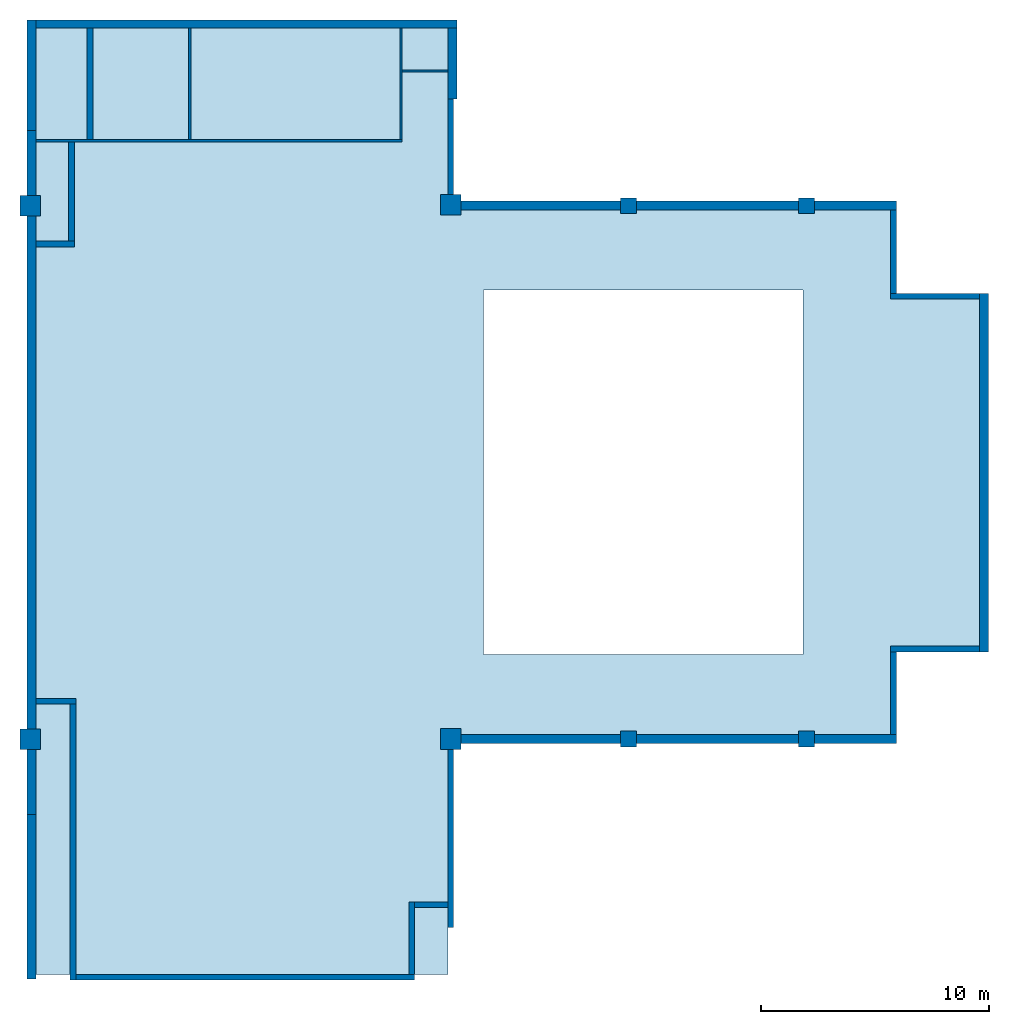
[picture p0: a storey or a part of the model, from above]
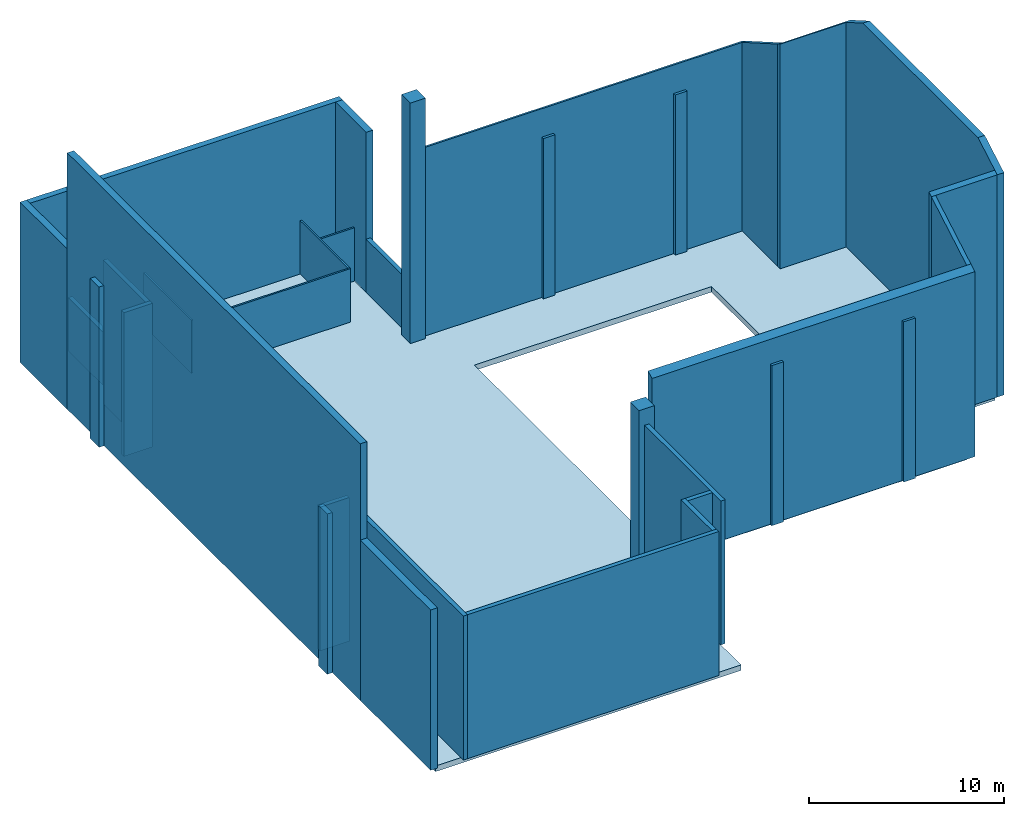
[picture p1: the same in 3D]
Properties of the parts of a building model (IFC2X3)

# File
Description: ViewDefinition [CoordinationView_V2.0], RevitIdentifiers [ContentGUID: 5fec9d22-f77b-40c9-8145-6ea0bd41274a, VersionGUID: 11239b1c-a36d-4747-897d-173505367494, NumberOfSaves: 46], CoordinateReference [CoordinateBase: Shared Coordinates, ProjectSite: NL_00_locatie]
File name: K176TT2132.ifc
Time: 2025-05-07T07:51:57+01:00
Written by: ODA SDAI 24.12
Made in: Autodesk Revit 25.4.10.45 (ENU) - IFC 25.4.10.45

# IfcProject, K176TT2132
LongName: Vervanging trekkenwand

# IfcSite, Default
RefLatitude: 52, 22, 22, 799999; RefLongitude: 4, 53, 41, 279999; RefElevation: 0 mm

# IfcBuilding
Pset_BuildingCommon - NumberOfStoreys: 6

# IfcBuildingStorey: Level:PBTA niveau met benaming (50)
Pset_AirSideSystemInformation - sets with these values: 2
Name | LongName = Name | Elevation (mm)
Peil | Peil | 0
Rij 1 | Rij 1 | 80
Rij 2 | Rij 2 | 160
Rij 3 | Rij 3 | 240
Rij 4 | Rij 4 | 320
Rij 5 | Rij 5 | 400
Rij 6 | Rij 6 | 480
Rij 7 | Rij 7 | 560
Rij 8 | Rij 8 | 640
Rij 9 | Rij 9 | 840
Rij 10 | Rij 10 | 1040
Rij 11 | Rij 11 | 1240
Rij 12 | Rij 12 | 1440
Rij 13 | Rij 13 | 1640
Rij 14 | Rij 14 | 1840
Rij 15 | Rij 15 | 2040
Rij 16 | Rij 16 | 2240
Rij 17 | Rij 17 | 2440
Rij 18 | Rij 18 | 2640
Rij 19 | Rij 19 | 2840
Rij 20 | Rij 20 | 3040
Rij 21 | Rij 21 | 3240
Rij 22 | Rij 22 | 3440
Rij 23 | Rij 23 | 3640
Rij 24 | Rij 24 | 3840
Rij 25 | Rij 25 | 4040
Balkon Rij 1 | Balkon Rij 1 | 5540
Balkon Rij 2 | Balkon Rij 2 | 5940
Balkon Rij 3 | Balkon Rij 3 | 6340
Balkon Rij 4 | Balkon Rij 4 | 6740
2e verdieping | 2e verdieping | 7050
Balkon Rij 5 | Balkon Rij 5 | 7140
Balkon Rij 6 | Balkon Rij 6 | 7540
Balkon Rij 7 | Balkon Rij 7 | 7940
Balkon Rij 8 | Balkon Rij 8 | 8340
Balkon Rij 9 | Balkon Rij 9 | 8740
Balkon Rij 10 | Balkon Rij 10 | 9140
Balkon Rij 11 | Balkon Rij 11 | 9540
Balkon Rij 12 | Balkon Rij 12 | 9940
Balkon Rij 13 | Balkon Rij 13 | 10340
3e verdieping | 3e verdieping | 10390
Balkon Rij 14 | Balkon Rij 14 | 10740
Balkon Rij 15 | Balkon Rij 15 | 11140
4e verdieping | 4e verdieping | 13730
5e verdieping | 5e verdieping | 17070
Dak binnendooszaal | Dak binnendooszaal | 22086.4
Dak zaal | Dak zaal | 23090
Rollenzolder | Rollenzolder | 30550
Dak toneeltoren | Dak toneeltoren | 33630
Dakrand toneeltoren | Dakrand toneeltoren | 34000

# IfcBeam: H-Balk:HEA140 (42)
Type - PredefinedType: BEAM
Type - Pset_BeamCommon - LoadBearing: yes
Material: Staal PBTA
Pset_BeamCommon - IsExternal: no; Slope: 0 deg; Reference: HEA140
Pset_QuantityTakeOff - Reference: HEA140; sets with these values: 2
Name (H-Balk:HEA140:...) | In | Span (mm)
577840 | Rollenzolder | 2960
578171 | Rollenzolder | 2960
578181 | Rollenzolder | 2960
578191 | Rollenzolder | 2960
578201 | Rollenzolder | 2960
578247 | Rollenzolder | 2960
578248 | Rollenzolder | 2960
578249 | Rollenzolder | 2960
578250 | Rollenzolder | 2960
578251 | Rollenzolder | 2960
579849 | Rollenzolder | 2958
579961 | Rollenzolder | 3017
579963 | Rollenzolder | 3017
579965 | Rollenzolder | 3017
579967 | Rollenzolder | 3017
579969 | Rollenzolder | 3017
579971 | Rollenzolder | 3017
579973 | Rollenzolder | 2958
579975 | Rollenzolder | 1517
580310 | Rollenzolder | 3017
580553 | Rollenzolder | 3017
580565 | Rollenzolder | 3017
580581 | Rollenzolder | 3017
580593 | Rollenzolder | 3017
580605 | Rollenzolder | 3017
580706 | Rollenzolder | 1517
642158 | Dak binnendooszaal | 2850
642609 | Dak binnendooszaal | 2850
642653 | Dak binnendooszaal | 2850
642667 | Dak binnendooszaal | 2850
642752 | Dak binnendooszaal | 2850
642753 | Dak binnendooszaal | 2850
642754 | Dak binnendooszaal | 2850
642755 | Dak binnendooszaal | 2850
642849 | Dak binnendooszaal | 2850
642850 | Dak binnendooszaal | 2850
642851 | Dak binnendooszaal | 2850
642852 | Dak binnendooszaal | 2850
642962 | Dak binnendooszaal | 2850
642963 | Dak binnendooszaal | 2850
642964 | Dak binnendooszaal | 2850
642965 | Dak binnendooszaal | 2850

# IfcBeam: H-Balk:HEA220 (4)
In: Dak binnendooszaal
Type - PredefinedType: BEAM
Type - Pset_BeamCommon - LoadBearing: yes
Material: Staal PBTA
Pset_BeamCommon - IsExternal: no; Slope: 0 deg; Reference: HEA220; Span: 5600 mm
Pset_QuantityTakeOff - Reference: HEA220; sets with these values: 2
Name (H-Balk:HEA220:...)
636427
636710
636720
636728

# IfcBeam: H-Balk:HEA240 (4)
In: Dak toneeltoren
Type - PredefinedType: BEAM
Type - Pset_BeamCommon - LoadBearing: yes
Material: Staal PBTA
Pset_BeamCommon - IsExternal: no; Reference: HEA240; Span: 29600 mm; Slope: 0 deg
Pset_QuantityTakeOff - Reference: HEA240; sets with these values: 2
Name (H-Balk:HEA240:...)
576049
576216
576222
576230

# IfcBeam: H-Balk:HEA300 (5)
In: Dak binnendooszaal
Type - PredefinedType: BEAM
Type - Pset_BeamCommon - LoadBearing: yes
Material: Staal PBTA
Pset_BeamCommon - IsExternal: no; Slope: 0 deg; Reference: HEA300; Span: 22745 mm
Pset_QuantityTakeOff - Reference: HEA300; sets with these values: 2
Name (H-Balk:HEA300:...)
627919
628030
628137
628199
628205

# IfcBeam: H-Balk:HEB240 (5)
In: Dak toneeltoren
Type - PredefinedType: BEAM
Type - Pset_BeamCommon - LoadBearing: yes
Material: Staal PBTA
Pset_BeamCommon - IsExternal: no; Slope: 0 deg; Reference: HEB240
Pset_QuantityTakeOff - Reference: HEB240; sets with these values: 2
Name (H-Balk:HEB240:...) | Span (mm)
576121 | 29600
576567 | 18200
576896 | 18200
576940 | 18200
576941 | 18200

# IfcBeam: IPE-Balk:IPE160 (134)
In: Rollenzolder
Type - PredefinedType: BEAM
Type - Pset_BeamCommon - LoadBearing: yes
Material: Staal PBTA
Pset_BeamCommon - IsExternal: no; Slope: 0 deg; Reference: IPE160
Pset_QuantityTakeOff - Reference: IPE160; sets with these values: 2
Name (IPE-Balk:IPE160:...) | Span (mm)
579442 | 2958
579553 | 2958
579662 | 1517
579663 | 1517
579728 | 3017
579729 | 3017
579780 | 3017
579781 | 3017
579789 | 3017
579790 | 3017
579800 | 3017
579801 | 3017
579809 | 3017
579810 | 3017
579822 | 3017
579823 | 3017
579850 | 2958
579851 | 1517
579852 | 1517
579878 | 2958
579879 | 2958
579880 | 1517
579881 | 1517
579882 | 3017
579883 | 3017
579884 | 3017
579885 | 3017
579886 | 3017
579887 | 3017
579888 | 3017
579889 | 3017
579890 | 3017
579891 | 3017
579892 | 3017
579893 | 3017
579894 | 2958
579895 | 2958
579896 | 1517
579897 | 1517
579905 | 2958
579906 | 2958
579907 | 1517
579908 | 1517
579909 | 3017
579910 | 3017
579911 | 3017
579912 | 3017
579913 | 3017
579914 | 3017
579915 | 3017
579916 | 3017
579917 | 3017
579918 | 3017
579919 | 3017
579920 | 3017
579921 | 2958
579922 | 2958
579923 | 1517
579924 | 1517
579930 | 2958
579931 | 2958
579932 | 1517
579933 | 1517
579934 | 3017
579935 | 3017
579936 | 3017
579937 | 3017
579938 | 3017
579939 | 3017
579940 | 3017
579941 | 3017
579942 | 3017
579943 | 3017
579944 | 3017
579945 | 3017
579946 | 2958
579947 | 2958
579948 | 1517
579949 | 1517
579957 | 2958
579959 | 1517
579999 | 2958
580000 | 2958
580001 | 1517
580002 | 1517
580003 | 3017
580004 | 3017
580005 | 3017
580006 | 3017
580007 | 3017
580008 | 3017
580009 | 3017
580010 | 3017
580011 | 3017
580012 | 3017
580013 | 3017
580014 | 3017
580015 | 2958
580016 | 2958
580017 | 1517
580018 | 1517
580399 | 1517
580400 | 1517
580401 | 1517
580402 | 1517
580403 | 1517
580485 | 3017
580486 | 3017
580487 | 3017
580488 | 3017
580554 | 3017
580555 | 3017
580556 | 3017
580557 | 3017
580566 | 3017
580567 | 3017
580568 | 3017
580569 | 3017
580582 | 3017
580583 | 3017
580584 | 3017
580585 | 3017
580594 | 3017
580595 | 3017
580596 | 3017
580597 | 3017
580606 | 3017
580607 | 3017
580608 | 3017
580609 | 3017
580703 | 1517
580704 | 1517
580705 | 1517
580707 | 1517

# IfcBuildingElementProxy: Decortrek Theater Rotterdam:L binnen (68)
In: Rollenzolder
Type - Material: Staal-PBTA, Staal-PBRI
Pset_BuildingElementProxyCommon - Reference: L binnen; sets with these values: 2
Name (Decortrek Theater Rotterdam:L binnen:...)
594433
595344
595345
595356
595357
595360
595361
595364
595365
595368
595369
595372
595373
595376
595377
595380
595381
595384
595385
595388
595389
595392
595393
595396
595397
595400
595401
595404
595405
595408
595409
595412
595413
595416
595417
595420
595421
595424
595425
595428
595429
595432
595433
595436
595437
595440
595441
595444
595445
595448
595449
595452
595453
595456
595457
595460
595461
595464
595465
595468
595469
595472
595473
595476
595477
595497
612826
612827

# IfcBuildingElementProxy: Lier bestaand:Lier centercluster, Lier bestaand:Lier centercluster:627696
In: 5e verdieping
Type - Material: Staal-PBRI
Pset_BuildingElementProxyCommon - Reference: Lier centercluster; sets with these values: 2

# IfcBuildingElementProxy: Lier bestaand:Lier portaalbrug, Lier bestaand:Lier portaalbrug:622974
In: Rollenzolder
Type - Material: Staal-PBRI
Pset_BuildingElementProxyCommon - Reference: Lier portaalbrug; sets with these values: 2

# IfcBuildingElementProxy: Proscenium trek Rotterdam:Proscenium trek Rotterdam, Proscenium trek Rotterdam:Proscenium trek Rotterdam:636032
In: Dak binnendooszaal
Type - Material: Staal-PBRI, Staal-PBTA
Pset_BuildingElementProxyCommon - Reference: Proscenium trek Rotterdam; sets with these values: 2

# IfcBuildingElementProxy: Spant:Spant (7)
In: Rollenzolder
Type - Material: Staal PBTA, <Unnamed>
Pset_BuildingElementProxyCommon - Reference: Spant; sets with these values: 2
Name (Spant:Spant:...)
569781
570149
570157
570165
570175
574750
574758

# IfcBuildingElementProxy: Zaaltrek Theater Rotterdam:Zaaltrek Theater Rotterdam (2)
In: Dak binnendooszaal
Type - Material: Staal-PBRI, Staal-PBTA
Pset_BuildingElementProxyCommon - Reference: Zaaltrek Theater Rotterdam; sets with these values: 2
Name (Zaaltrek Theater Rotterdam:Zaaltrek Theater Rotterdam:...)
606188
606455

# IfcBuildingElementProxy: Zijtrek Theater Rotterdam:R binnen (2)
In: Rollenzolder
Type - Material: Staal-PBRI, Staal-PBTA
Pset_BuildingElementProxyCommon - Reference: R binnen; sets with these values: 2
Name (Zijtrek Theater Rotterdam:R binnen:...)
618984
621021

# IfcBuildingElementProxy: Zijtrek Theater Rotterdam:R buiten (2)
In: Rollenzolder
Type - Material: Staal-PBRI, Staal-PBTA
Pset_BuildingElementProxyCommon - Reference: R buiten; sets with these values: 2
Name (Zijtrek Theater Rotterdam:R buiten:...)
619524
621022

# IfcBuildingElementProxy: ophanging:ophanging (2)
In: Rollenzolder
Type - Material: Staal PBTA
Pset_BuildingElementProxyCommon - Reference: ophanging; sets with these values: 2
Name (ophanging:ophanging:...)
574341
574693

# IfcColumn: Koker-Kolom:K80/80/4CF (8)
In: Dak binnendooszaal
Type - PredefinedType: COLUMN; Material: Staal PBTA
Type - Pset_ColumnCommon - LoadBearing: yes
Pset_ColumnCommon - IsExternal: no; Reference: K80/80/4CF
Pset_QuantityTakeOff - Reference: K80/80/4CF; sets with these values: 2
Name (Koker-Kolom:K80/80/4CF:...)
637413
637721
637804
637805
637818
637819
637836
637837

# IfcColumn: M_Concrete-Square-Column:700 x 700mm (4)
In: 2e verdieping
Type - PredefinedType: COLUMN; Material: Concrete, Cast-in-Place gray
Type - Pset_ColumnCommon - LoadBearing: yes
Pset_ColumnCommon - IsExternal: no; Reference: 700 x 700mm
Pset_QuantityTakeOff - Reference: 700 x 700mm; sets with these values: 2
Name (M_Concrete-Square-Column:700 x 700mm:...)
588921
589097
589205
589206

# IfcColumn: M_Concrete-Square-Column:900 x 900 (4)
In: 2e verdieping
Type - PredefinedType: COLUMN; Material: Concrete, Cast-in-Place gray
Type - Pset_ColumnCommon - LoadBearing: yes
Pset_ColumnCommon - IsExternal: no; Reference: 900 x 900
Pset_QuantityTakeOff - Reference: 900 x 900; sets with these values: 2
Name (M_Concrete-Square-Column:900 x 900:...)
563383
563395
563466
563523

# IfcDistributionPort (2)
Description: Flow; FlowDirection: SOURCEANDSINK
Name
Port_632358_0
Port_632358_1

# IfcDoor: Binnendeur enkel:780x2115, Binnendeur enkel:780x2115:598546
In: Rollenzolder
Type - OperationType: SINGLE_SWING_LEFT; ParameterTakesPrecedence: no; Sizeable: no; Material: Kozijn, Deur
Type - Binnendeur enkel:780x2115:598546:1 - PanelOperation: SWINGING
OverallHeight: 2187 mm; OverallWidth: 884 mm
Pset_DoorCommon - IsExternal: no; Reference: 780x2115
Pset_QuantityTakeOff - Reference: 780x2115

# IfcDoor: Binnendeur enkel:780x2115 (3)
In: Rollenzolder
Type - OperationType: SINGLE_SWING_RIGHT; ParameterTakesPrecedence: no; Sizeable: no; Material: Kozijn, Deur
Type - Binnendeur enkel:780x2115:598288:1 - PanelOperation: SWINGING
OverallHeight: 2187 mm; OverallWidth: 884 mm
Pset_DoorCommon - IsExternal: no; Reference: 780x2115
Pset_QuantityTakeOff - Reference: 780x2115
Name (Binnendeur enkel:780x2115:...)
598288
598549
599045

# IfcFlowSegment: Cable Tray without Fittings:Wire Mesh Cable Tray, Cable Tray without Fittings:Wire Mesh Cable Tray:632358
In: Dak binnendooszaal
Type - PredefinedType: CABLETRAYSEGMENT
Pset_DistributionFlowElementCommon - Reference: Wire Mesh Cable Tray; sets with these values: 2
Pset_FlowSegmentDuctSegment - Length: 10700 mm; sets with these values: 2

# IfcOpeningElement: Opening (5)
Name | In
Floor:NL_23 Toneelvloer:145068 | 2e verdieping | Pset_OpeningElementCommon - Reference: NL_23 Toneelvloer; sets with these values: 2
Binnendeur enkel:780x2115:598288:1 | Rollenzolder
Binnendeur enkel:780x2115:598549:1 | Rollenzolder
Binnendeur enkel:780x2115:598546:1 | Rollenzolder
Binnendeur enkel:780x2115:599045:1 | Rollenzolder

# IfcRoof: Basic Roof:NL_27_basis_200 (4)
Material: NL_27_dak 200 mm
Pset_QuantityTakeOff - Reference: NL_27_basis_200
Pset_RoofCommon - IsExternal: yes; Reference: NL_27_basis_200
Name (Basic Roof:NL_27_basis_200:...) | In | ProjectedArea (m2) | TotalArea (m2)
561494 | Dak binnendooszaal | 273.581 | 273.581
587362 | Dak toneeltoren | 547.748 | 547.748
600069 | Dak binnendooszaal | 123.194 | 142.252
600201 | Dak binnendooszaal | 123.268 | 142.338

# IfcSlab: Basic Roof:NL_27_basis_200 (4)
PredefinedType: ROOF; Material: NL_27_dak 200 mm
Pset_QuantityTakeOff - Reference: NL_27_basis_200; sets with these values: 2
Pset_SlabCommon - IsExternal: yes; Reference: NL_27_basis_200
Name (Basic Roof:NL_27_basis_200:...) | In | PitchAngle (deg)
561494 | Dak binnendooszaal | 0
587362 | Dak toneeltoren | 0
600069 | Dak binnendooszaal | 30
600201 | Dak binnendooszaal | 30

# IfcSlab: Floor:NL_23 Rooster bruggen (4)
In: 5e verdieping
Type - PredefinedType: FLOOR; Material: Roostervloer dicht 30 mm
Pset_QuantityTakeOff - Reference: NL_23 Rooster bruggen; sets with these values: 2
Pset_SlabCommon - LoadBearing: no; IsExternal: no; PitchAngle: 0 deg; Reference: NL_23 Rooster bruggen
Name (Floor:NL_23 Rooster bruggen:...)
599056
599094
599273
599353

# IfcSlab: Floor:NL_23 Toneelvloer, Floor:NL_23 Toneelvloer:563597
In: 2e verdieping
Type - PredefinedType: FLOOR; Material: NL_45 Keroewing 22 mm, NL_45 Multiplex 18 mm, NL_45 isolatie + regelwerk 10 mm, NL_23 Kanaalplaatvloer 300 mm
Pset_QuantityTakeOff - Reference: NL_23 Toneelvloer; sets with these values: 2
Pset_SlabCommon - LoadBearing: no; IsExternal: no; PitchAngle: 0 deg; Reference: NL_23 Toneelvloer

# IfcWallStandardCase: Basic Wall:AL_20_basis_100 (4)
In: 2e verdieping
Type - PredefinedType: STANDARD; Material: NL_20_wand 100 mm
Pset_QuantityTakeOff - Reference: AL_20_basis_100; sets with these values: 2
Pset_WallCommon - LoadBearing: no; IsExternal: no; ExtendToStructure: no; Reference: AL_20_basis_100
Name (Basic Wall:AL_20_basis_100:...)
562058
562084
562090
562096

# IfcWallStandardCase: Basic Wall:AL_20_basis_140 (3)
In: Rollenzolder
Type - PredefinedType: STANDARD; Material: NL_20_wand 140 mm
Pset_QuantityTakeOff - Reference: AL_20_basis_140; sets with these values: 2
Pset_WallCommon - LoadBearing: no; IsExternal: no; ExtendToStructure: no; Reference: AL_20_basis_140
Name (Basic Wall:AL_20_basis_140:...)
596048
596184
598545

# IfcWallStandardCase: Basic Wall:AL_20_basis_200 (4)
In: Dak zaal
Type - PredefinedType: STANDARD; Material: NL_20_wand 200 mm
Pset_QuantityTakeOff - Reference: AL_20_basis_200; sets with these values: 2
Pset_WallCommon - LoadBearing: no; IsExternal: no; ExtendToStructure: no; Reference: AL_20_basis_200
Name (Basic Wall:AL_20_basis_200:...)
586774
586775
586776
586777

# IfcWallStandardCase: Basic Wall:AL_20_basis_220 (8)
In: 2e verdieping
Type - PredefinedType: STANDARD; Material: NL_20_wand 250 mm
Pset_QuantityTakeOff - Reference: AL_20_basis_220; sets with these values: 2
Pset_WallCommon - LoadBearing: no; IsExternal: no; ExtendToStructure: no; Reference: AL_20_basis_220
Name (Basic Wall:AL_20_basis_220:...)
561925
561931
561973
561979
561989
562024
562030
562154

# IfcWallStandardCase: Basic Wall:AL_20_basis_250 (6)
In: 2e verdieping
Type - PredefinedType: STANDARD; Material: NL_20_wand 250 mm
Pset_QuantityTakeOff - Reference: AL_20_basis_250; sets with these values: 2
Pset_WallCommon - LoadBearing: no; Reference: AL_20_basis_250; IsExternal: no
Name (Basic Wall:AL_20_basis_250:...) | ExtendToStructure
561391 | yes
561397 | yes
561432 | yes
561433 | yes
562014 | no
562213 | no

# IfcWallStandardCase: Basic Wall:AL_20_basis_350, Basic Wall:AL_20_basis_350:561757
In: 2e verdieping
Type - PredefinedType: STANDARD; Material: NL_20_wand 350 mm
Pset_QuantityTakeOff - Reference: AL_20_basis_350; sets with these values: 2
Pset_WallCommon - IsExternal: yes; LoadBearing: no; ExtendToStructure: no; Reference: AL_20_basis_350

# IfcWallStandardCase: Basic Wall:AL_20_basis_400 (8)
Type - PredefinedType: STANDARD; Material: NL_20_wand 400 mm
Pset_QuantityTakeOff - Reference: AL_20_basis_400; sets with these values: 2
Pset_WallCommon - Reference: AL_20_basis_400; IsExternal: yes; LoadBearing: no
Name (Basic Wall:AL_20_basis_400:...) | In | ExtendToStructure
561343 | 2e verdieping | yes
561349 | 2e verdieping | yes
561431 | 2e verdieping | yes
561751 | 2e verdieping | no
561841 | 2e verdieping | no
577314 | 2e verdieping | no
577433 | 5e verdieping | no
577598 | 2e verdieping | no
